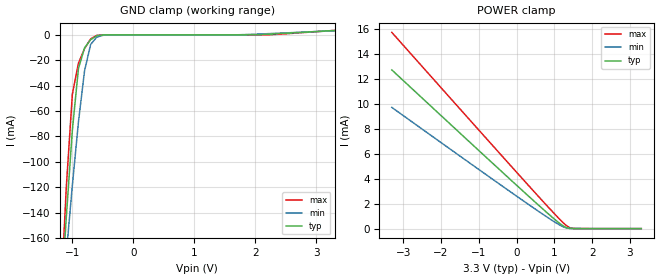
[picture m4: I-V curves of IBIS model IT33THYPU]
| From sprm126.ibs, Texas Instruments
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[Model]   IT33THYPU
Model_type   Input
Polarity   Non-Inverting
| signals   A, Y
Vinl = 0.8V
Vinh = 2.0V
|   typ   min   max
C_comp   1.5797p   1.5046p   1.7659p
|   typ   min   max
[Temperature Range]   25   -40   125
|   typ   min   max
[Voltage Range]   3.30V   3.00V   3.60V
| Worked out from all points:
|   GND clamp passes 1 mA (typ) near -0.61 V on its own axis
[GND_clamp]
|   Voltage   I(typ)   I(min)   I(max)
-3.3V     -2.001A    -1.513A    -2.596A
-1.2V     -220.6mA   -229.5mA   -218.7mA
-1.1V     -144.2mA   -172.9mA   -120.6mA
-1V       -75.08mA   -118.6mA   -46.8mA
-900mV    -26.54mA   -68.59mA   -22.23mA
-800mV    -10.21mA   -28.31mA   -10.8mA
-700mV    -3.767mA   -7.524mA   -3.181mA
-600mV    -734.6uA   -1.835mA   -363.9uA
-400mV    -3.756uA   -40.45uA   -379.8nA
1.6V      1.998uA    10.91uA    674.2nA
2.2V      515.8uA    940.4uA    84.84uA
3.3V      3.487mA    3.251mA    3.522mA
[POWER_clamp]
|   Voltage   I(typ)   I(min)   I(max)
-3.3V     12.75mA    9.735mA    15.76mA
300mV     2.657mA    1.977mA    3.522mA
1V        767.5uA    546.5uA    1.2mA
1.3V      100.6uA    70.16uA    285.4uA
1.4V      17.88uA    13.68uA    83.7uA
1.5V      5.457uA    2.621uA    15.29uA
3.3V      -178.8pA   -3.889uA   -49.96pA
